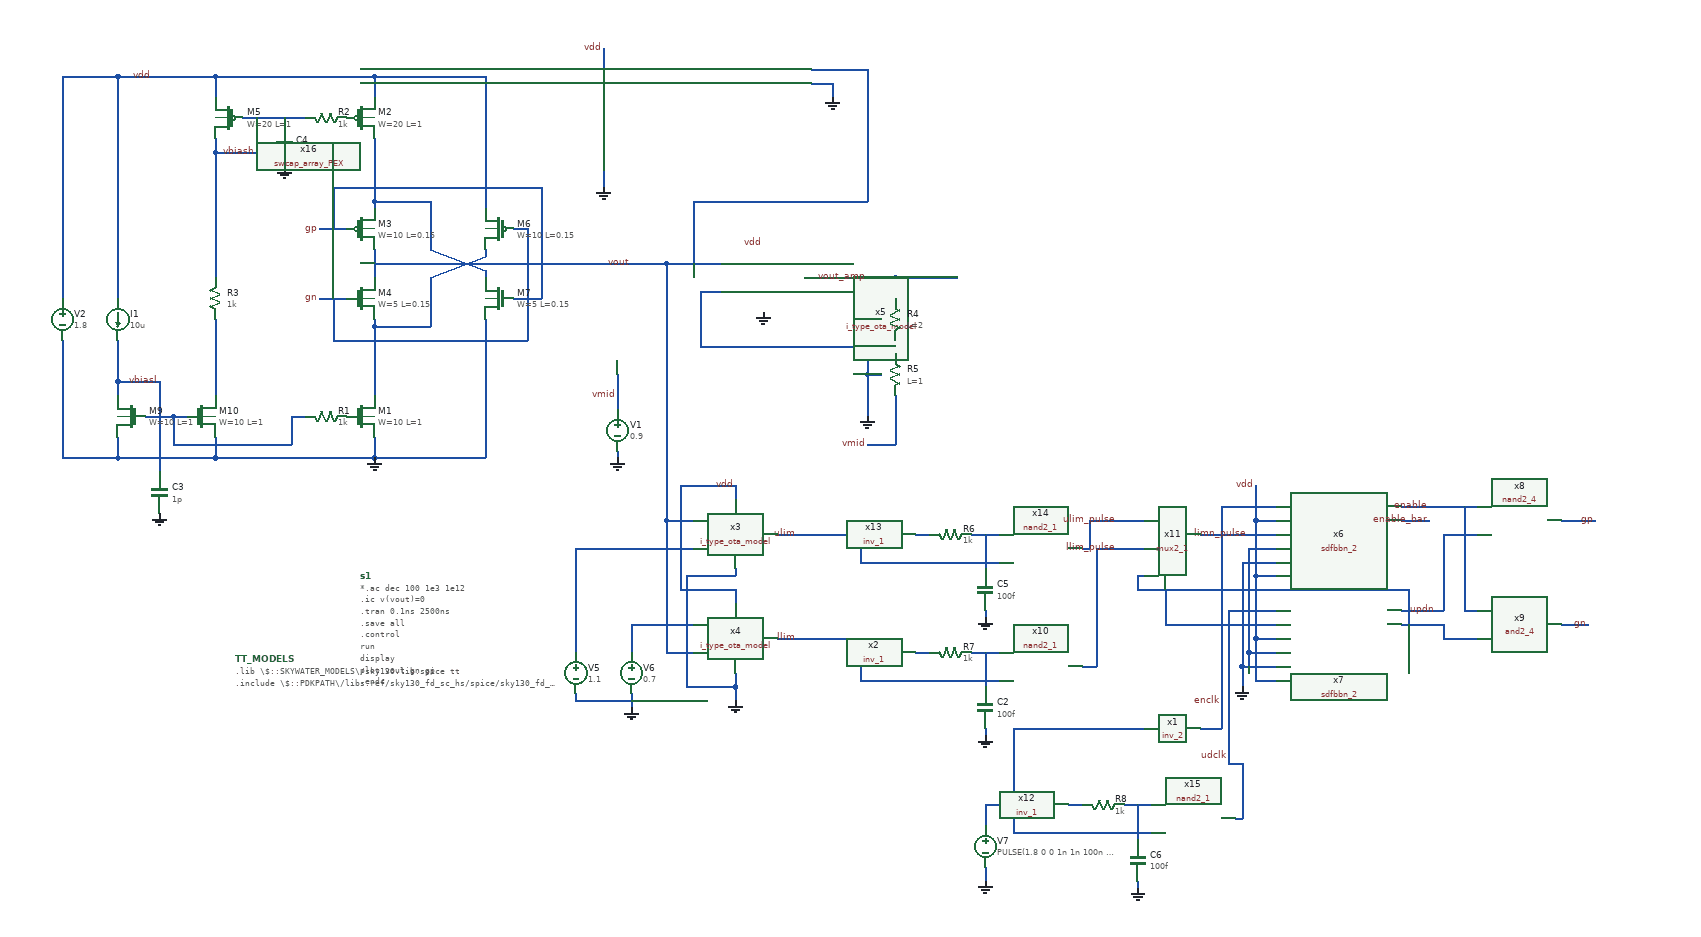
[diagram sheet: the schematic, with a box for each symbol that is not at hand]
v {xschem version=3.1.0 file_version=1.2
}
G {}
K {}
V {}
S {}
E {}
N 440 -10 440 0 {
lab=GND}
N 90 -110 90 -90 {
lab=#net1}
N 610 190 610 210 {
lab=vdd}
N 530 190 610 190 {
lab=vdd}
N 530 40 530 190 {
lab=vdd}
N 530 40 610 40 {
lab=vdd}
N 610 40 610 60 {
lab=vdd}
N 610 160 610 170 {
lab=GND}
N 540 170 610 170 {
lab=GND}
N 540 170 540 330 {
lab=GND}
N 540 330 610 330 {
lab=GND}
N 610 310 610 330 {
lab=GND}
N 610 330 610 350 {
lab=GND}
N 470 130 550 130 {
lab=#net2}
N 510 90 510 280 {
lab=vout}
N 510 280 550 280 {
lab=vout}
N 460 240 460 280 {
lab=#net3}
N 380 130 380 280 {
lab=#net2}
N 380 130 470 130 {
lab=#net2}
N 460 240 550 240 {
lab=#net3}
N 460 340 460 360 {
lab=GND}
N 380 340 380 350 {
lab=GND}
N 380 350 460 350 {
lab=GND}
N 700 110 710 110 {
lab=ulim}
N 700 260 710 260 {
lab=llim}
N 1360 90 1380 90 {
lab=vdd}
N 970 590 970 610 {
lab=GND}
N 1570 70 1620 70 {
lab=enable}
N 1370 240 1390 240 {
lab=#net4}
N 1570 240 1600 240 {
lab=#net4}
N 1570 220 1630 220 {
lab=updn}
N 1380 90 1390 90 {
lab=vdd}
N 1620 70 1680 70 {
lab=enable}
N 1660 70 1660 220 {
lab=enable}
N 1660 220 1680 220 {
lab=enable}
N 1640 110 1680 110 {
lab=updn}
N 1630 110 1630 220 {
lab=updn}
N 1630 110 1640 110 {
lab=updn}
N 1600 240 1630 240 {
lab=#net4}
N 1630 240 1630 260 {
lab=#net4}
N 1630 260 1680 260 {
lab=#net4}
N 1800 90 1850 90 {
lab=gp}
N 1800 240 1840 240 {
lab=gn}
N 1350 280 1390 280 {
lab=GND}
N 1350 130 1350 280 {
lab=GND}
N 1350 130 1390 130 {
lab=GND}
N 1340 150 1390 150 {
lab=GND}
N 1340 150 1340 300 {
lab=GND}
N 1340 300 1390 300 {
lab=GND}
N 1340 300 1340 330 {
lab=GND}
N 1330 70 1390 70 {
lab=enclk}
N 1360 40 1360 90 {
lab=vdd}
N 1360 170 1390 170 {
lab=vdd}
N 1280 110 1390 110 {
lab=limn_pulse}
N 1310 70 1310 130 {
lab=enclk}
N 1310 70 1330 70 {
lab=enclk}
N 390 -280 460 -280 {
lab=vout}
N 510 90 550 90 {
lab=vout}
N 510 -280 510 90 {
lab=vout}
N 460 -280 510 -280 {
lab=vout}
N 440 -120 440 -70 {
lab=vmid}
N 670 110 700 110 {
lab=ulim}
N 670 260 700 260 {
lab=llim}
N 1570 90 1610 90 {
lab=enable_bar}
N 1350 280 1350 300 {
lab=GND}
N 970 110 970 160 {
lab=#net5}
N 970 220 970 230 {
lab=GND}
N 790 150 990 150 {
lab=ulim}
N 790 110 790 150 {
lab=ulim}
N 870 110 890 110 {
lab=#net6}
N 950 110 990 110 {
lab=#net5}
N 1360 90 1360 170 {
lab=vdd}
N 710 260 720 260 {
lab=llim}
N 710 110 720 110 {
lab=ulim}
N 1150 390 1200 390 {
lab=#net7}
N 1310 130 1310 390 {
lab=enclk}
N 1320 220 1320 440 {
lab=udclk}
N 1320 220 1390 220 {
lab=udclk}
N 1360 260 1390 260 {
lab=vdd}
N 1360 170 1360 260 {
lab=vdd}
N 1360 260 1360 320 {
lab=vdd}
N 1360 320 1390 320 {
lab=vdd}
N 1230 240 1370 240 {
lab=#net4}
N 1110 130 1120 130 {
lab=ulim_pulse}
N 1280 390 1310 390 {
lab=enclk}
N 90 -550 90 -520 {
lab=vdd}
N 10 -230 50 -230 {
lab=gn}
N 10 -330 50 -330 {
lab=gp}
N -40 -490 -40 -480 {
lab=vbiash}
N -100 -490 -10 -490 {
lab=vbiash}
N -80 -490 -80 -440 {
lab=vbiash}
N -140 -440 -80 -440 {
lab=vbiash}
N -140 -460 -140 -440 {
lab=vbiash}
N -140 -550 -140 -520 {
lab=vdd}
N -140 -550 90 -550 {
lab=vdd}
N -30 -60 -10 -60 {
lab=vbiasl}
N -200 -60 -180 -60 {
lab=vbiasl}
N -140 -30 -140 0 {
lab=GND}
N 90 -30 90 0 {
lab=GND}
N -140 0 90 0 {
lab=GND}
N -200 -60 -200 -20 {
lab=vbiasl}
N -200 -20 -30 -20 {
lab=vbiasl}
N -30 -60 -30 -20 {
lab=vbiasl}
N -240 -60 -200 -60 {
lab=vbiasl}
N -280 -30 -280 0 {
lab=GND}
N -280 0 -140 0 {
lab=GND}
N -220 -110 -220 -60 {
lab=vbiasl}
N -280 -110 -220 -110 {
lab=vbiasl}
N -280 -110 -280 -90 {
lab=vbiasl}
N -220 -60 -220 20 {
lab=vbiasl}
N -280 -170 -280 -110 {
lab=vbiasl}
N -280 -550 -280 -230 {
lab=vdd}
N -280 -550 -140 -550 {
lab=vdd}
N -360 -170 -360 0 {
lab=GND}
N -360 0 -280 0 {
lab=GND}
N -360 -550 -360 -230 {
lab=vdd}
N -360 -550 -280 -550 {
lab=vdd}
N -140 -200 -140 -90 {
lab=#net8}
N -140 -440 -140 -260 {
lab=vbiash}
N 840 -170 840 -150 {
lab=#net9}
N 800 -200 820 -200 {
lab=GND}
N 800 -200 800 -120 {
lab=GND}
N 800 -120 820 -120 {
lab=GND}
N 800 -120 800 -60 {
lab=GND}
N 840 -260 840 -230 {
lab=vout_amp}
N 710 -260 840 -260 {
lab=vout_amp}
N 510 -280 590 -280 {
lab=vout}
N 560 -240 590 -240 {
lab=#net9}
N 560 -160 840 -160 {
lab=#net9}
N 560 -240 560 -160 {
lab=#net9}
N 800 -20 840 -20 {
lab=vmid}
N 840 -90 840 -20 {
lab=vmid}
N 840 -260 930 -260 {
lab=vout_amp}
N 720 110 790 110 {
lab=ulim}
N 970 280 970 330 {
lab=#net10}
N 970 390 970 400 {
lab=GND}
N 790 320 990 320 {
lab=llim}
N 790 280 790 320 {
lab=llim}
N 870 280 890 280 {
lab=#net11}
N 950 280 990 280 {
lab=#net10}
N 1110 300 1120 300 {
lab=llim_pulse}
N 720 260 790 260 {
lab=llim}
N 790 260 790 280 {
lab=llim}
N 1120 90 1120 130 {
lab=ulim_pulse}
N 1120 90 1200 90 {
lab=ulim_pulse}
N 1130 130 1200 130 {
lab=llim_pulse}
N 1130 130 1130 300 {
lab=llim_pulse}
N 1120 300 1130 300 {
lab=llim_pulse}
N 1190 170 1200 170 {
lab=#net4}
N 1190 170 1190 190 {
lab=#net4}
N 1190 190 1580 190 {
lab=#net4}
N 1580 190 1580 240 {
lab=#net4}
N 1230 190 1230 240 {
lab=#net4}
N 1190 500 1190 550 {
lab=#net12}
N 1190 610 1190 620 {
lab=GND}
N 1010 540 1210 540 {
lab=#net7}
N 1010 500 1010 540 {
lab=#net7}
N 1090 500 1110 500 {
lab=#net13}
N 1170 500 1210 500 {
lab=#net12}
N 1330 520 1340 520 {
lab=udclk}
N 1010 480 1010 500 {
lab=#net7}
N 1340 440 1340 520 {
lab=udclk}
N 1320 440 1340 440 {
lab=udclk}
N 1010 390 1010 480 {
lab=#net7}
N 1010 390 1150 390 {
lab=#net7}
N 90 -300 90 -260 {
lab=vout}
N 250 -300 250 -290 {
lab=#net1}
N 170 -260 250 -290 {
lab=#net1}
N 250 -270 250 -260 {
lab=#net14}
N 170 -300 250 -270 {
lab=#net14}
N 170 -260 170 -190 {
lab=#net1}
N 90 -190 170 -190 {
lab=#net1}
N 90 -200 90 -190 {
lab=#net1}
N 170 -370 170 -300 {
lab=#net14}
N 90 -370 170 -370 {
lab=#net14}
N 90 -370 90 -360 {
lab=#net14}
N 250 -490 250 -360 {
lab=vdd}
N 250 -200 250 -120 {
lab=GND}
N 30 -390 30 -330 {
lab=gp}
N 30 -390 330 -390 {
lab=gp}
N 330 -390 330 -230 {
lab=gp}
N 290 -230 330 -230 {
lab=gp}
N 290 -330 310 -330 {
lab=gn}
N 310 -330 310 -170 {
lab=gn}
N 30 -170 310 -170 {
lab=gn}
N 30 -230 30 -170 {
lab=gn}
N 90 -460 90 -370 {
lab=#net14}
N 90 -190 90 -110 {
lab=#net1}
N 250 -120 250 0 {
lab=GND}
N 90 0 250 0 {
lab=GND}
N 90 -550 250 -550 {
lab=vdd}
N 250 -550 250 -490 {
lab=vdd}
N 90 -280 390 -280 {
lab=vout}
N 970 500 970 530 {
lab=#net7}
N 970 500 1010 500 {
lab=#net7}
N 750 -540 750 -520 {
lab=GND}
N 720 -540 750 -540 {
lab=GND}
N 720 -560 800 -560 {
lab=vout}
N 800 -560 800 -370 {
lab=vout}
N 550 -370 800 -370 {
lab=vout}
N 550 -370 550 -280 {
lab=vout}
N 420 -540 420 -390 {
lab=GND}
N 420 -590 420 -560 {
lab=vdd}
C {sky130_fd_pr/nfet3_01v8.sym} 70 -60 0 0 {name=M1
L=1
W=10
body=GND
nf=1
mult=1
ad="'int((nf+1)/2) * W/nf * 0.29'" 
pd="'2*int((nf+1)/2) * (W/nf + 0.29)'"
as="'int((nf+2)/2) * W/nf * 0.29'" 
ps="'2*int((nf+2)/2) * (W/nf + 0.29)'"
nrd="'0.29 / W'" nrs="'0.29 / W'"
sa=0 sb=0 sd=0
model=nfet_01v8
spiceprefix=X
}
C {sky130_fd_pr/pfet3_01v8.sym} 70 -490 0 0 {name=M2
L=1
W=20
body=VDD
nf=1
mult=1
ad="'int((nf+1)/2) * W/nf * 0.29'" 
pd="'2*int((nf+1)/2) * (W/nf + 0.29)'"
as="'int((nf+2)/2) * W/nf * 0.29'" 
ps="'2*int((nf+2)/2) * (W/nf + 0.29)'"
nrd="'0.29 / W'" nrs="'0.29 / W'"
sa=0 sb=0 sd=0
model=pfet_01v8
spiceprefix=X
}
C {sky130_fd_pr/pfet3_01v8.sym} 70 -330 0 0 {name=M3
L=0.15
W=10
body=VDD
nf=1
mult=1
ad="'int((nf+1)/2) * W/nf * 0.29'" 
pd="'2*int((nf+1)/2) * (W/nf + 0.29)'"
as="'int((nf+2)/2) * W/nf * 0.29'" 
ps="'2*int((nf+2)/2) * (W/nf + 0.29)'"
nrd="'0.29 / W'" nrs="'0.29 / W'"
sa=0 sb=0 sd=0
model=pfet_01v8
spiceprefix=X
}
C {sky130_fd_pr/nfet3_01v8.sym} 70 -230 0 0 {name=M4
L=0.15
W=5
body=GND
nf=1
mult=1
ad="'int((nf+1)/2) * W/nf * 0.29'" 
pd="'2*int((nf+1)/2) * (W/nf + 0.29)'"
as="'int((nf+2)/2) * W/nf * 0.29'" 
ps="'2*int((nf+2)/2) * (W/nf + 0.29)'"
nrd="'0.29 / W'" nrs="'0.29 / W'"
sa=0 sb=0 sd=0
model=nfet_01v8
spiceprefix=X
}
C {devices/gnd.sym} 90 0 0 0 {name=l1 lab=GND}
C {devices/gnd.sym} 440 0 0 0 {name=l2 lab=GND}
C {devices/vsource.sym} 440 -40 0 0 {name=V1 value=0.9}
C {devices/vsource.sym} -360 -200 0 0 {name=V2 value=1.8}
C {sky130_fd_pr/pfet3_01v8.sym} -120 -490 0 1 {name=M5
L=1
W=20
body=VDD
nf=1
mult=1
ad="'int((nf+1)/2) * W/nf * 0.29'" 
pd="'2*int((nf+1)/2) * (W/nf + 0.29)'"
as="'int((nf+2)/2) * W/nf * 0.29'" 
ps="'2*int((nf+2)/2) * (W/nf + 0.29)'"
nrd="'0.29 / W'" nrs="'0.29 / W'"
sa=0 sb=0 sd=0
model=pfet_01v8
spiceprefix=X
}
C {devices/isource.sym} -280 -200 0 0 {name=I1 value=10u}
C {devices/lab_wire.sym} -230 -550 0 0 {name=p1 sig_type=std_logic lab=vdd}
C {devices/lab_wire.sym} 460 -280 0 0 {name=p2 sig_type=std_logic lab=vout}
C {devices/lab_wire.sym} 10 -230 0 0 {name=p3 sig_type=std_logic lab=gn}
C {devices/code.sym} -110 290 0 0 {name=TT_MODELS only_toplevel=false
format="tcleval(@value )" value=".lib \\\\$::SKYWATER_MODELS\\\\/sky130.lib.spice tt
.include \\\\$::PDKPATH\\\\/libs.ref/sky130_fd_sc_hs/spice/sky130_fd_sc_hs.spice"}
C {devices/code_shown.sym} 70 170 0 0 {name=s1
only_toplevel=false
value="
*.ac dec 100 1e3 1e12
.ic v(vout)=0
.tran 0.1ns 2500ns
.save all
.control
run
display
plot vout gn gp
.endc
"}
C {devices/lab_wire.sym} 10 -330 0 0 {name=p4 sig_type=std_logic lab=gp}
C {devices/lab_wire.sym} -220 -110 0 0 {name=p5 sig_type=std_logic lab=vbiasl}
C {devices/lab_wire.sym} -80 -440 0 0 {name=p6 sig_type=std_logic lab=vbiash}
C {devices/res.sym} 20 -60 1 0 {name=R1
value=1k
footprint=1206
device=resistor
m=1}
C {devices/res.sym} 20 -490 1 0 {name=R2
value=1k
footprint=1206
device=resistor
m=1}
C {devices/lab_wire.sym} 610 40 0 0 {name=p7 sig_type=std_logic lab=vdd}
C {devices/gnd.sym} 610 350 0 0 {name=l5 lab=GND}
C {devices/lab_wire.sym} 700 110 0 0 {name=p8 sig_type=std_logic lab=ulim}
C {devices/lab_wire.sym} 700 260 0 0 {name=p9 sig_type=std_logic lab=llim}
C {devices/vsource.sym} 380 310 0 0 {name=V5 value="1.1"}
C {devices/vsource.sym} 460 310 0 0 {name=V6 value="0.7"}
C {devices/gnd.sym} 460 360 0 0 {name=l7 lab=GND}
C {sky130_stdcells/sdfbbn_2.sym} 1480 120 0 0 {name=x6 VGND=gnd VNB=gnd VPB=vdd VPWR=vdd prefix=sky130_fd_sc_hs__ 
}
C {devices/lab_wire.sym} 1360 40 0 0 {name=p11 sig_type=std_logic lab=vdd}
C {devices/vsource.sym} 970 560 0 0 {name=V7 value="PULSE(1.8 0 0 1n 1n 100n 200n)"}
C {devices/gnd.sym} 970 610 0 0 {name=l8 lab=GND}
C {devices/lab_wire.sym} 1310 350 0 0 {name=p12 sig_type=std_logic lab=enclk}
C {devices/lab_wire.sym} 1610 70 0 0 {name=p13 sig_type=std_logic lab=enable}
C {sky130_stdcells/sdfbbn_2.sym} 1480 270 0 0 {name=x7 VGND=gnd VNB=gnd VPB=vdd VPWR=vdd prefix=sky130_fd_sc_hs__ 
}
C {devices/lab_wire.sym} 1620 220 0 0 {name=p15 sig_type=std_logic lab=updn}
C {sky130_stdcells/nand2_4.sym} 1740 90 0 0 {name=x8 VGND=gnd VNB=gnd VPB=vdd VPWR=vdd prefix=sky130_fd_sc_hs__ }
C {sky130_stdcells/and2_4.sym} 1740 240 0 0 {name=x9 VGND=gnd VNB=gnd VPB=vdd VPWR=vdd prefix=sky130_fd_sc_hs__ 
}
C {devices/lab_wire.sym} 1850 90 0 0 {name=p16 sig_type=std_logic lab=gp}
C {devices/lab_wire.sym} 1840 240 0 0 {name=p17 sig_type=std_logic lab=gn}
C {devices/gnd.sym} 1340 330 0 0 {name=l9 lab=GND}
C {devices/lab_wire.sym} 440 -90 0 0 {name=p18 sig_type=std_logic lab=vmid}
C {devices/lab_wire.sym} 1610 90 0 0 {name=p20 sig_type=std_logic lab=enable_bar}
C {devices/lab_wire.sym} 1350 110 0 0 {name=p21 sig_type=std_logic lab=limn_pulse}
C {sky130_stdcells/inv_2.sym} 1240 390 0 0 {name=x1 VGND=gnd VNB=gnd VPB=vdd VPWR=vdd prefix=sky130_fd_sc_hs__ 
}
C {devices/res.sym} 920 110 1 0 {name=R6
value=1k
footprint=1206
device=resistor
m=1}
C {devices/capa.sym} 970 190 0 0 {name=C5
m=1
value=100f
footprint=1206
device="ceramic capacitor"}
C {devices/gnd.sym} 970 230 0 0 {name=l10 lab=GND}
C {sky130_stdcells/inv_1.sym} 830 110 0 0 {name=x13 VGND=gnd VNB=gnd VPB=vdd VPWR=vdd prefix=sky130_fd_sc_hs__ 
}
C {sky130_stdcells/nand2_1.sym} 1050 130 0 0 {name=x14 VGND=gnd VNB=gnd VPB=vdd VPWR=vdd prefix=sky130_fd_sc_hs__ 
}
C {devices/capa.sym} -40 -450 0 0 {name=C4
m=1
value=1p
footprint=1206
device="ceramic capacitor"}
C {devices/gnd.sym} -40 -420 0 0 {name=l3 lab=GND}
C {sky130_fd_pr/nfet3_01v8.sym} -160 -60 0 0 {name=M10
L=1
W=10
body=GND
nf=1
mult=1
ad="'int((nf+1)/2) * W/nf * 0.29'" 
pd="'2*int((nf+1)/2) * (W/nf + 0.29)'"
as="'int((nf+2)/2) * W/nf * 0.29'" 
ps="'2*int((nf+2)/2) * (W/nf + 0.29)'"
nrd="'0.29 / W'" nrs="'0.29 / W'"
sa=0 sb=0 sd=0
model=nfet_01v8
spiceprefix=X
}
C {sky130_fd_pr/nfet3_01v8.sym} -260 -60 0 1 {name=M9
L=1
W=10
body=GND
nf=1
mult=1
ad="'int((nf+1)/2) * W/nf * 0.29'" 
pd="'2*int((nf+1)/2) * (W/nf + 0.29)'"
as="'int((nf+2)/2) * W/nf * 0.29'" 
ps="'2*int((nf+2)/2) * (W/nf + 0.29)'"
nrd="'0.29 / W'" nrs="'0.29 / W'"
sa=0 sb=0 sd=0
model=nfet_01v8
spiceprefix=X
}
C {devices/capa.sym} -220 50 0 0 {name=C3
m=1
value=1p
footprint=1206
device="ceramic capacitor"}
C {devices/gnd.sym} -220 80 0 0 {name=l11 lab=GND}
C {devices/res.sym} -140 -230 2 0 {name=R3
value=1k
footprint=1206
device=resistor
m=1}
C {i_type_ota_model.sym} 610 110 0 0 {name=x3}
C {i_type_ota_model.sym} 610 260 0 0 {name=x4}
C {i_type_ota_model.sym} 650 -260 0 0 {name=x5}
C {devices/lab_wire.sym} 650 -310 0 0 {name=p10 sig_type=std_logic lab=vdd}
C {devices/gnd.sym} 650 -210 0 0 {name=l4 lab=GND}
C {sky130_fd_pr/res_xhigh_po_0p35.sym} 840 -200 0 0 {name=R4
L=2
model=res_xhigh_po_0p35
spiceprefix=X
mult=1}
C {sky130_fd_pr/res_xhigh_po_0p35.sym} 840 -120 0 0 {name=R5
L=1
model=res_xhigh_po_0p35
spiceprefix=X
mult=1}
C {devices/gnd.sym} 800 -60 0 0 {name=l6 lab=GND}
C {devices/lab_wire.sym} 800 -20 0 0 {name=p14 sig_type=std_logic lab=vmid}
C {devices/lab_wire.sym} 800 -260 0 0 {name=p19 sig_type=std_logic lab=vout_amp}
C {devices/res.sym} 920 280 1 0 {name=R7
value=1k
footprint=1206
device=resistor
m=1}
C {devices/capa.sym} 970 360 0 0 {name=C2
m=1
value=100f
footprint=1206
device="ceramic capacitor"}
C {devices/gnd.sym} 970 400 0 0 {name=l12 lab=GND}
C {sky130_stdcells/inv_1.sym} 830 280 0 0 {name=x2 VGND=gnd VNB=gnd VPB=vdd VPWR=vdd prefix=sky130_fd_sc_hs__ 
}
C {sky130_stdcells/nand2_1.sym} 1050 300 0 0 {name=x10 VGND=gnd VNB=gnd VPB=vdd VPWR=vdd prefix=sky130_fd_sc_hs__ 
}
C {sky130_stdcells/mux2_1.sym} 1240 110 0 0 {name=x11 VGND=gnd VNB=gnd VPB=vdd VPWR=vdd prefix=sky130_fd_sc_hs__ 
}
C {devices/lab_wire.sym} 1160 90 0 0 {name=p23 sig_type=std_logic lab=ulim_pulse}
C {devices/lab_wire.sym} 1160 130 0 0 {name=p24 sig_type=std_logic lab=llim_pulse}
C {devices/res.sym} 1140 500 1 0 {name=R8
value=1k
footprint=1206
device=resistor
m=1}
C {devices/capa.sym} 1190 580 0 0 {name=C6
m=1
value=100f
footprint=1206
device="ceramic capacitor"}
C {devices/gnd.sym} 1190 620 0 0 {name=l13 lab=GND}
C {sky130_stdcells/inv_1.sym} 1050 500 0 0 {name=x12 VGND=gnd VNB=gnd VPB=vdd VPWR=vdd prefix=sky130_fd_sc_hs__ 
}
C {sky130_stdcells/nand2_1.sym} 1270 520 0 0 {name=x15 VGND=gnd VNB=gnd VPB=vdd VPWR=vdd prefix=sky130_fd_sc_hs__ 
}
C {devices/lab_wire.sym} 1320 430 0 0 {name=p22 sig_type=std_logic lab=udclk}
C {sky130_fd_pr/pfet3_01v8.sym} 270 -330 0 1 {name=M6
L=0.15
W=10
body=VDD
nf=1
mult=1
ad="'int((nf+1)/2) * W/nf * 0.29'" 
pd="'2*int((nf+1)/2) * (W/nf + 0.29)'"
as="'int((nf+2)/2) * W/nf * 0.29'" 
ps="'2*int((nf+2)/2) * (W/nf + 0.29)'"
nrd="'0.29 / W'" nrs="'0.29 / W'"
sa=0 sb=0 sd=0
model=pfet_01v8
spiceprefix=X
}
C {sky130_fd_pr/nfet3_01v8.sym} 270 -230 0 1 {name=M7
L=0.15
W=5
body=GND
nf=1
mult=1
ad="'int((nf+1)/2) * W/nf * 0.29'" 
pd="'2*int((nf+1)/2) * (W/nf + 0.29)'"
as="'int((nf+2)/2) * W/nf * 0.29'" 
ps="'2*int((nf+2)/2) * (W/nf + 0.29)'"
nrd="'0.29 / W'" nrs="'0.29 / W'"
sa=0 sb=0 sd=0
model=nfet_01v8
spiceprefix=X
}
C {swcap_array_PEX.sym} 570 -490 0 0 {name=x16}
C {devices/gnd.sym} 750 -520 0 0 {name=l14 lab=GND}
C {devices/gnd.sym} 420 -390 0 0 {name=l15 lab=GND}
C {devices/lab_wire.sym} 420 -590 0 0 {name=p25 sig_type=std_logic lab=vdd}
